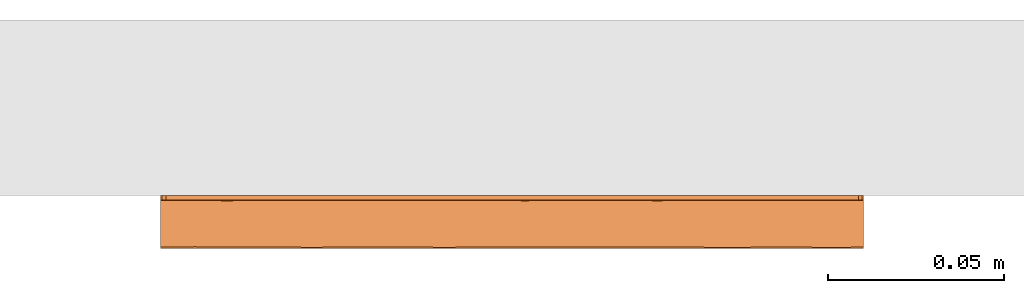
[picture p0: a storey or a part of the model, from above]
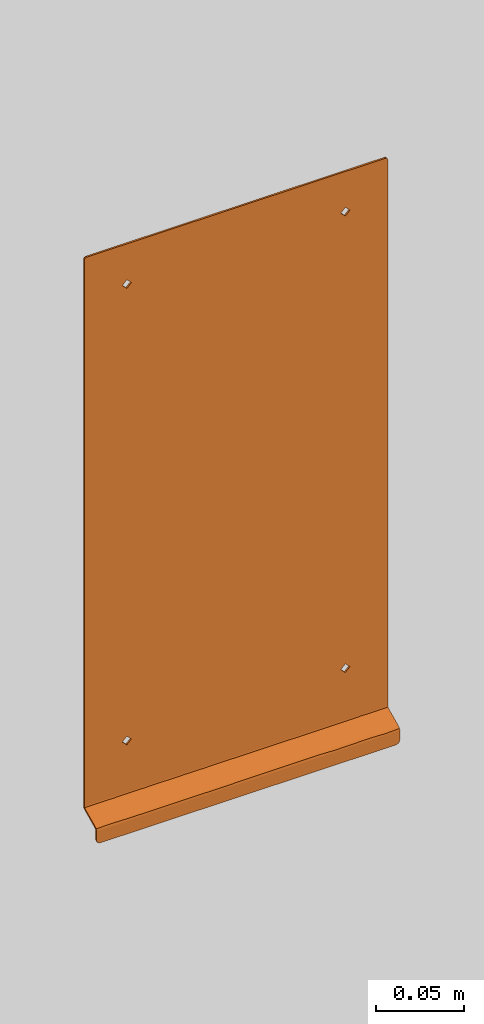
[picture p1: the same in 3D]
Properties of the parts of a building model (IFC2X3)

# File
Description: ViewDefinition [CoordinationView]
Time: 2018-01-16T15:23:48
Written by: The EXPRESS Data Manager Version 5.01.0100.02.64mod : 6 Jun 2012
Made in: 20140709_2115(x64) - Exporter 2014.0.2014.0709 - Default UI
Comment: STEP Physical File produced by: The EXPRESS Data Manager Version 5.01.0100.02.64mod : 6 Jun 2012 * Module: EDMstepFileFactory/EDMstandAlone * Creation date: Tue Jan 16 15:23:48 2018 * Host: BIM-HP * Database: C:\Users\dcole\AppData\Local\Temp\{311D9DD2-8658-4242-8728-D977410F5DFB}\ifc * Database version: 5507 * Database creation date: Tue Jan 16 15:23:46 2018 * Schema: IFC2X3 * Model: DataRepository.ifc * Model creation date: Tue Jan 16 15:23:47 2018 * Header model: DataRepository.ifc_HeaderModel * Header model creation date: Tue Jan 16 15:23:47 2018 * EDMuser: sdai-user * EDMgroup: sdai-group * License ID and type: 5605 : Permanent license. Expiry date: * EDMstepFileFactory options: 020000

# IfcProject
LongName: P:\Fastrack\53721_DOLPHIN SOLUTIONS LIMITED\ADDITIONAL DRAWINGS 2018 BIM\IFC\BC2000.ifc

# IfcSite, Default
RefLatitude: 42, 24, 53, 508911; RefLongitude: -71, -15, -29, -58837; RefElevation: 0 mm

# IfcBuilding
Pset_BuildingCommon - NumberOfStoreys: 1

# IfcBuildingStorey, Level 1
LongName: Level 1; Elevation: 0 mm
Constraints - Elevation Base: Project Base Point; Elevation: 0 mm
Identity Data - Structural: no; Name: Level 1; Building Story: yes
Dimensions - Computation Height: 0 mm
Graphics - Symbol at End 1 Default: no; Symbol at End 2 Default: yes; Color: 0; Line Pattern: -3000010; Line Weight: 1

# IfcBuildingElementProxy: BC2000 Dolphin Splash Panel, BC2000-200mm:BC2000 Dolphin Splash Panel:68696
In: Level 1
Phasing - Phase Created: New Construction
Constraints - Moves With Nearby Elements: no; Offset: 327.388 mm; Level: Level: Level 1; Host: Level : Level 1
Dimensions - Volume: 0.0000978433 m3; Width: 200mm; Height: 400mm; Projection: 15mm
Pset_ManufacturerTypeInformation - Manufacturer: Dolphin Solutions Ltd.
Pset_BuildingElementProxyCommon - Reference: BC2000 Dolphin Splash Panel
Identity Data - URL: www.dolphinsolutions.co.uk; Tel No.: +44 (0) 1424 202 224; Assembly Code: D2010900; Description: Splash panel; Email: info@dolphinsolutions.co.uk; Model: BC2000; Assembly Description: Other Plumbing Fixtures; Fax No.: +44 (0) 1424 205 200; Manufacturer: Dolphin Solutions Ltd.; Address: Southpoint, Compass Park, Junction Road, Bodiam, TN32 5BS
General - Product Data: High quality stainless steel. Unique drip detail to throw water off the wall. Eliminates the staining caused by water-run common with high speed dryers. Available in three finishes to match the bulk of the hand dryer range: satin stainless steel, polished stainless steel and white metal (white powder coated).; Product Page Link: https://www.dolphinsolutions.co.uk/en/product/splash-panel
Materials and Finishes - Material: 1.2mm Stainless steel

# IfcWallStandardCase: Basic Wall:Wall 1, Basic Wall:Wall 1:3092
In: Level 1
Type - PredefinedType: STANDARD; Material: Default Wall 50 mm
Type - Analytical Properties - Absorptance: 0.1; Roughness: 1
Type - Construction - Width: 50 mm; Wrapping at Inserts: Do not wrap; Function: Exterior
Type - Graphics - Coarse Scale Fill Color: 8454143
Constraints - Unconnected Height: 936.967 mm; Top Offset: 0 mm; Base Offset: 0 mm; Top is Attached: no; Base Constraint: Level: Level 1; Base is Attached: no; Room Bounding: yes; Base Extension Distance: 0 mm; Related to Mass: no; Top Extension Distance: 0 mm; Location Line: Finish Face: Interior
Phasing - Phase Created: New Construction
Structural - Structural: no; Enable Analytical Model: no; Structural Usage: Non-bearing
Dimensions - Area: 0.599659 m2; Volume: 0.0299829 m3; Length: 640 mm
Pset_WallCommon - Reference: Wall 1; LoadBearing: no; ExtendToStructure: no; IsExternal: yes
